VERSION 5.7 ;
BUSBITCHARS "[]" ;
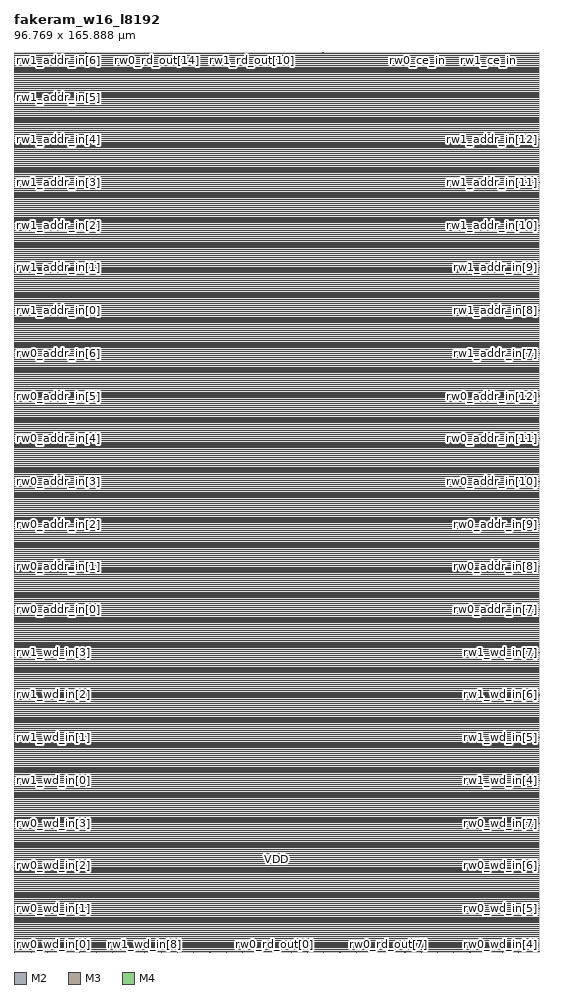
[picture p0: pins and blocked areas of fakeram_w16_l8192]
MACRO fakeram_w16_l8192
  FOREIGN fakeram_w16_l8192 0 0 ;
  SYMMETRY X Y R90 ;
  SIZE 96.769 BY 165.888 ;
  CLASS BLOCK ;
  PIN rw0_wd_in[0]
    DIRECTION INPUT ;
    USE SIGNAL ;
    SHAPE ABUTMENT ;
    PORT
      LAYER M2 ;
      RECT 0.000 0.138 0.036 0.150 ;
    END
  END rw0_wd_in[0]
  PIN rw0_wd_in[1]
    DIRECTION INPUT ;
    USE SIGNAL ;
    SHAPE ABUTMENT ;
    PORT
      LAYER M2 ;
      RECT 0.000 8.010 0.036 8.022 ;
    END
  END rw0_wd_in[1]
  PIN rw0_wd_in[2]
    DIRECTION INPUT ;
    USE SIGNAL ;
    SHAPE ABUTMENT ;
    PORT
      LAYER M2 ;
      RECT 0.000 15.882 0.036 15.894 ;
    END
  END rw0_wd_in[2]
  PIN rw0_wd_in[3]
    DIRECTION INPUT ;
    USE SIGNAL ;
    SHAPE ABUTMENT ;
    PORT
      LAYER M2 ;
      RECT 0.000 23.754 0.036 23.766 ;
    END
  END rw0_wd_in[3]
  PIN rw0_wd_in[4]
    DIRECTION INPUT ;
    USE SIGNAL ;
    SHAPE ABUTMENT ;
    PORT
      LAYER M2 ;
      RECT 96.733 0.138 96.769 0.150 ;
    END
  END rw0_wd_in[4]
  PIN rw0_wd_in[5]
    DIRECTION INPUT ;
    USE SIGNAL ;
    SHAPE ABUTMENT ;
    PORT
      LAYER M2 ;
      RECT 96.733 8.010 96.769 8.022 ;
    END
  END rw0_wd_in[5]
  PIN rw0_wd_in[6]
    DIRECTION INPUT ;
    USE SIGNAL ;
    SHAPE ABUTMENT ;
    PORT
      LAYER M2 ;
      RECT 96.733 15.882 96.769 15.894 ;
    END
  END rw0_wd_in[6]
  PIN rw0_wd_in[7]
    DIRECTION INPUT ;
    USE SIGNAL ;
    SHAPE ABUTMENT ;
    PORT
      LAYER M2 ;
      RECT 96.733 23.754 96.769 23.766 ;
    END
  END rw0_wd_in[7]
  PIN rw0_wd_in[8]
    DIRECTION INPUT ;
    USE SIGNAL ;
    SHAPE ABUTMENT ;
    PORT
      LAYER M3 ;
      RECT 0.161 0.000 0.175 0.042 ;
    END
  END rw0_wd_in[8]
  PIN rw0_wd_in[9]
    DIRECTION INPUT ;
    USE SIGNAL ;
    SHAPE ABUTMENT ;
    PORT
      LAYER M3 ;
      RECT 3.157 0.000 3.171 0.042 ;
    END
  END rw0_wd_in[9]
  PIN rw0_wd_in[10]
    DIRECTION INPUT ;
    USE SIGNAL ;
    SHAPE ABUTMENT ;
    PORT
      LAYER M3 ;
      RECT 6.153 0.000 6.167 0.042 ;
    END
  END rw0_wd_in[10]
  PIN rw0_wd_in[11]
    DIRECTION INPUT ;
    USE SIGNAL ;
    SHAPE ABUTMENT ;
    PORT
      LAYER M3 ;
      RECT 9.149 0.000 9.163 0.042 ;
    END
  END rw0_wd_in[11]
  PIN rw0_wd_in[12]
    DIRECTION INPUT ;
    USE SIGNAL ;
    SHAPE ABUTMENT ;
    PORT
      LAYER M3 ;
      RECT 12.145 0.000 12.159 0.042 ;
    END
  END rw0_wd_in[12]
  PIN rw0_wd_in[13]
    DIRECTION INPUT ;
    USE SIGNAL ;
    SHAPE ABUTMENT ;
    PORT
      LAYER M3 ;
      RECT 15.141 0.000 15.155 0.042 ;
    END
  END rw0_wd_in[13]
  PIN rw0_wd_in[14]
    DIRECTION INPUT ;
    USE SIGNAL ;
    SHAPE ABUTMENT ;
    PORT
      LAYER M3 ;
      RECT 18.137 0.000 18.151 0.042 ;
    END
  END rw0_wd_in[14]
  PIN rw0_wd_in[15]
    DIRECTION INPUT ;
    USE SIGNAL ;
    SHAPE ABUTMENT ;
    PORT
      LAYER M3 ;
      RECT 21.133 0.000 21.147 0.042 ;
    END
  END rw0_wd_in[15]
  PIN rw1_wd_in[0]
    DIRECTION INPUT ;
    USE SIGNAL ;
    SHAPE ABUTMENT ;
    PORT
      LAYER M2 ;
      RECT 0.000 31.626 0.036 31.638 ;
    END
  END rw1_wd_in[0]
  PIN rw1_wd_in[1]
    DIRECTION INPUT ;
    USE SIGNAL ;
    SHAPE ABUTMENT ;
    PORT
      LAYER M2 ;
      RECT 0.000 39.498 0.036 39.510 ;
    END
  END rw1_wd_in[1]
  PIN rw1_wd_in[2]
    DIRECTION INPUT ;
    USE SIGNAL ;
    SHAPE ABUTMENT ;
    PORT
      LAYER M2 ;
      RECT 0.000 47.370 0.036 47.382 ;
    END
  END rw1_wd_in[2]
  PIN rw1_wd_in[3]
    DIRECTION INPUT ;
    USE SIGNAL ;
    SHAPE ABUTMENT ;
    PORT
      LAYER M2 ;
      RECT 0.000 55.242 0.036 55.254 ;
    END
  END rw1_wd_in[3]
  PIN rw1_wd_in[4]
    DIRECTION INPUT ;
    USE SIGNAL ;
    SHAPE ABUTMENT ;
    PORT
      LAYER M2 ;
      RECT 96.733 31.626 96.769 31.638 ;
    END
  END rw1_wd_in[4]
  PIN rw1_wd_in[5]
    DIRECTION INPUT ;
    USE SIGNAL ;
    SHAPE ABUTMENT ;
    PORT
      LAYER M2 ;
      RECT 96.733 39.498 96.769 39.510 ;
    END
  END rw1_wd_in[5]
  PIN rw1_wd_in[6]
    DIRECTION INPUT ;
    USE SIGNAL ;
    SHAPE ABUTMENT ;
    PORT
      LAYER M2 ;
      RECT 96.733 47.370 96.769 47.382 ;
    END
  END rw1_wd_in[6]
  PIN rw1_wd_in[7]
    DIRECTION INPUT ;
    USE SIGNAL ;
    SHAPE ABUTMENT ;
    PORT
      LAYER M2 ;
      RECT 96.733 55.242 96.769 55.254 ;
    END
  END rw1_wd_in[7]
  PIN rw1_wd_in[8]
    DIRECTION INPUT ;
    USE SIGNAL ;
    SHAPE ABUTMENT ;
    PORT
      LAYER M3 ;
      RECT 24.129 0.000 24.143 0.042 ;
    END
  END rw1_wd_in[8]
  PIN rw1_wd_in[9]
    DIRECTION INPUT ;
    USE SIGNAL ;
    SHAPE ABUTMENT ;
    PORT
      LAYER M3 ;
      RECT 27.125 0.000 27.139 0.042 ;
    END
  END rw1_wd_in[9]
  PIN rw1_wd_in[10]
    DIRECTION INPUT ;
    USE SIGNAL ;
    SHAPE ABUTMENT ;
    PORT
      LAYER M3 ;
      RECT 30.121 0.000 30.135 0.042 ;
    END
  END rw1_wd_in[10]
  PIN rw1_wd_in[11]
    DIRECTION INPUT ;
    USE SIGNAL ;
    SHAPE ABUTMENT ;
    PORT
      LAYER M3 ;
      RECT 33.117 0.000 33.131 0.042 ;
    END
  END rw1_wd_in[11]
  PIN rw1_wd_in[12]
    DIRECTION INPUT ;
    USE SIGNAL ;
    SHAPE ABUTMENT ;
    PORT
      LAYER M3 ;
      RECT 36.113 0.000 36.127 0.042 ;
    END
  END rw1_wd_in[12]
  PIN rw1_wd_in[13]
    DIRECTION INPUT ;
    USE SIGNAL ;
    SHAPE ABUTMENT ;
    PORT
      LAYER M3 ;
      RECT 39.109 0.000 39.123 0.042 ;
    END
  END rw1_wd_in[13]
  PIN rw1_wd_in[14]
    DIRECTION INPUT ;
    USE SIGNAL ;
    SHAPE ABUTMENT ;
    PORT
      LAYER M3 ;
      RECT 42.105 0.000 42.119 0.042 ;
    END
  END rw1_wd_in[14]
  PIN rw1_wd_in[15]
    DIRECTION INPUT ;
    USE SIGNAL ;
    SHAPE ABUTMENT ;
    PORT
      LAYER M3 ;
      RECT 45.101 0.000 45.115 0.042 ;
    END
  END rw1_wd_in[15]
  PIN rw0_rd_out[0]
    DIRECTION OUTPUT ;
    USE SIGNAL ;
    SHAPE ABUTMENT ;
    PORT
      LAYER M3 ;
      RECT 48.097 0.000 48.111 0.042 ;
    END
  END rw0_rd_out[0]
  PIN rw0_rd_out[1]
    DIRECTION OUTPUT ;
    USE SIGNAL ;
    SHAPE ABUTMENT ;
    PORT
      LAYER M3 ;
      RECT 51.093 0.000 51.107 0.042 ;
    END
  END rw0_rd_out[1]
  PIN rw0_rd_out[2]
    DIRECTION OUTPUT ;
    USE SIGNAL ;
    SHAPE ABUTMENT ;
    PORT
      LAYER M3 ;
      RECT 54.089 0.000 54.103 0.042 ;
    END
  END rw0_rd_out[2]
  PIN rw0_rd_out[3]
    DIRECTION OUTPUT ;
    USE SIGNAL ;
    SHAPE ABUTMENT ;
    PORT
      LAYER M3 ;
      RECT 57.085 0.000 57.099 0.042 ;
    END
  END rw0_rd_out[3]
  PIN rw0_rd_out[4]
    DIRECTION OUTPUT ;
    USE SIGNAL ;
    SHAPE ABUTMENT ;
    PORT
      LAYER M3 ;
      RECT 60.081 0.000 60.095 0.042 ;
    END
  END rw0_rd_out[4]
  PIN rw0_rd_out[5]
    DIRECTION OUTPUT ;
    USE SIGNAL ;
    SHAPE ABUTMENT ;
    PORT
      LAYER M3 ;
      RECT 63.077 0.000 63.091 0.042 ;
    END
  END rw0_rd_out[5]
  PIN rw0_rd_out[6]
    DIRECTION OUTPUT ;
    USE SIGNAL ;
    SHAPE ABUTMENT ;
    PORT
      LAYER M3 ;
      RECT 66.073 0.000 66.087 0.042 ;
    END
  END rw0_rd_out[6]
  PIN rw0_rd_out[7]
    DIRECTION OUTPUT ;
    USE SIGNAL ;
    SHAPE ABUTMENT ;
    PORT
      LAYER M3 ;
      RECT 69.069 0.000 69.083 0.042 ;
    END
  END rw0_rd_out[7]
  PIN rw0_rd_out[8]
    DIRECTION OUTPUT ;
    USE SIGNAL ;
    SHAPE ABUTMENT ;
    PORT
      LAYER M3 ;
      RECT 0.161 165.846 0.175 165.888 ;
    END
  END rw0_rd_out[8]
  PIN rw0_rd_out[9]
    DIRECTION OUTPUT ;
    USE SIGNAL ;
    SHAPE ABUTMENT ;
    PORT
      LAYER M3 ;
      RECT 4.529 165.846 4.543 165.888 ;
    END
  END rw0_rd_out[9]
  PIN rw0_rd_out[10]
    DIRECTION OUTPUT ;
    USE SIGNAL ;
    SHAPE ABUTMENT ;
    PORT
      LAYER M3 ;
      RECT 8.897 165.846 8.911 165.888 ;
    END
  END rw0_rd_out[10]
  PIN rw0_rd_out[11]
    DIRECTION OUTPUT ;
    USE SIGNAL ;
    SHAPE ABUTMENT ;
    PORT
      LAYER M3 ;
      RECT 13.265 165.846 13.279 165.888 ;
    END
  END rw0_rd_out[11]
  PIN rw0_rd_out[12]
    DIRECTION OUTPUT ;
    USE SIGNAL ;
    SHAPE ABUTMENT ;
    PORT
      LAYER M3 ;
      RECT 17.633 165.846 17.647 165.888 ;
    END
  END rw0_rd_out[12]
  PIN rw0_rd_out[13]
    DIRECTION OUTPUT ;
    USE SIGNAL ;
    SHAPE ABUTMENT ;
    PORT
      LAYER M3 ;
      RECT 22.001 165.846 22.015 165.888 ;
    END
  END rw0_rd_out[13]
  PIN rw0_rd_out[14]
    DIRECTION OUTPUT ;
    USE SIGNAL ;
    SHAPE ABUTMENT ;
    PORT
      LAYER M3 ;
      RECT 26.369 165.846 26.383 165.888 ;
    END
  END rw0_rd_out[14]
  PIN rw0_rd_out[15]
    DIRECTION OUTPUT ;
    USE SIGNAL ;
    SHAPE ABUTMENT ;
    PORT
      LAYER M3 ;
      RECT 30.737 165.846 30.751 165.888 ;
    END
  END rw0_rd_out[15]
  PIN rw1_rd_out[0]
    DIRECTION OUTPUT ;
    USE SIGNAL ;
    SHAPE ABUTMENT ;
    PORT
      LAYER M3 ;
      RECT 72.065 0.000 72.079 0.042 ;
    END
  END rw1_rd_out[0]
  PIN rw1_rd_out[1]
    DIRECTION OUTPUT ;
    USE SIGNAL ;
    SHAPE ABUTMENT ;
    PORT
      LAYER M3 ;
      RECT 75.061 0.000 75.075 0.042 ;
    END
  END rw1_rd_out[1]
  PIN rw1_rd_out[2]
    DIRECTION OUTPUT ;
    USE SIGNAL ;
    SHAPE ABUTMENT ;
    PORT
      LAYER M3 ;
      RECT 78.057 0.000 78.071 0.042 ;
    END
  END rw1_rd_out[2]
  PIN rw1_rd_out[3]
    DIRECTION OUTPUT ;
    USE SIGNAL ;
    SHAPE ABUTMENT ;
    PORT
      LAYER M3 ;
      RECT 81.053 0.000 81.067 0.042 ;
    END
  END rw1_rd_out[3]
  PIN rw1_rd_out[4]
    DIRECTION OUTPUT ;
    USE SIGNAL ;
    SHAPE ABUTMENT ;
    PORT
      LAYER M3 ;
      RECT 84.049 0.000 84.063 0.042 ;
    END
  END rw1_rd_out[4]
  PIN rw1_rd_out[5]
    DIRECTION OUTPUT ;
    USE SIGNAL ;
    SHAPE ABUTMENT ;
    PORT
      LAYER M3 ;
      RECT 87.045 0.000 87.059 0.042 ;
    END
  END rw1_rd_out[5]
  PIN rw1_rd_out[6]
    DIRECTION OUTPUT ;
    USE SIGNAL ;
    SHAPE ABUTMENT ;
    PORT
      LAYER M3 ;
      RECT 90.041 0.000 90.055 0.042 ;
    END
  END rw1_rd_out[6]
  PIN rw1_rd_out[7]
    DIRECTION OUTPUT ;
    USE SIGNAL ;
    SHAPE ABUTMENT ;
    PORT
      LAYER M3 ;
      RECT 93.037 0.000 93.051 0.042 ;
    END
  END rw1_rd_out[7]
  PIN rw1_rd_out[8]
    DIRECTION OUTPUT ;
    USE SIGNAL ;
    SHAPE ABUTMENT ;
    PORT
      LAYER M3 ;
      RECT 35.105 165.846 35.119 165.888 ;
    END
  END rw1_rd_out[8]
  PIN rw1_rd_out[9]
    DIRECTION OUTPUT ;
    USE SIGNAL ;
    SHAPE ABUTMENT ;
    PORT
      LAYER M3 ;
      RECT 39.473 165.846 39.487 165.888 ;
    END
  END rw1_rd_out[9]
  PIN rw1_rd_out[10]
    DIRECTION OUTPUT ;
    USE SIGNAL ;
    SHAPE ABUTMENT ;
    PORT
      LAYER M3 ;
      RECT 43.841 165.846 43.855 165.888 ;
    END
  END rw1_rd_out[10]
  PIN rw1_rd_out[11]
    DIRECTION OUTPUT ;
    USE SIGNAL ;
    SHAPE ABUTMENT ;
    PORT
      LAYER M3 ;
      RECT 48.209 165.846 48.223 165.888 ;
    END
  END rw1_rd_out[11]
  PIN rw1_rd_out[12]
    DIRECTION OUTPUT ;
    USE SIGNAL ;
    SHAPE ABUTMENT ;
    PORT
      LAYER M3 ;
      RECT 52.577 165.846 52.591 165.888 ;
    END
  END rw1_rd_out[12]
  PIN rw1_rd_out[13]
    DIRECTION OUTPUT ;
    USE SIGNAL ;
    SHAPE ABUTMENT ;
    PORT
      LAYER M3 ;
      RECT 56.945 165.846 56.959 165.888 ;
    END
  END rw1_rd_out[13]
  PIN rw1_rd_out[14]
    DIRECTION OUTPUT ;
    USE SIGNAL ;
    SHAPE ABUTMENT ;
    PORT
      LAYER M3 ;
      RECT 61.313 165.846 61.327 165.888 ;
    END
  END rw1_rd_out[14]
  PIN rw1_rd_out[15]
    DIRECTION OUTPUT ;
    USE SIGNAL ;
    SHAPE ABUTMENT ;
    PORT
      LAYER M3 ;
      RECT 65.681 165.846 65.695 165.888 ;
    END
  END rw1_rd_out[15]
  PIN rw0_addr_in[0]
    DIRECTION INPUT ;
    USE SIGNAL ;
    SHAPE ABUTMENT ;
    PORT
      LAYER M2 ;
      RECT 0.000 63.114 0.036 63.126 ;
    END
  END rw0_addr_in[0]
  PIN rw0_addr_in[1]
    DIRECTION INPUT ;
    USE SIGNAL ;
    SHAPE ABUTMENT ;
    PORT
      LAYER M2 ;
      RECT 0.000 70.986 0.036 70.998 ;
    END
  END rw0_addr_in[1]
  PIN rw0_addr_in[2]
    DIRECTION INPUT ;
    USE SIGNAL ;
    SHAPE ABUTMENT ;
    PORT
      LAYER M2 ;
      RECT 0.000 78.858 0.036 78.870 ;
    END
  END rw0_addr_in[2]
  PIN rw0_addr_in[3]
    DIRECTION INPUT ;
    USE SIGNAL ;
    SHAPE ABUTMENT ;
    PORT
      LAYER M2 ;
      RECT 0.000 86.730 0.036 86.742 ;
    END
  END rw0_addr_in[3]
  PIN rw0_addr_in[4]
    DIRECTION INPUT ;
    USE SIGNAL ;
    SHAPE ABUTMENT ;
    PORT
      LAYER M2 ;
      RECT 0.000 94.602 0.036 94.614 ;
    END
  END rw0_addr_in[4]
  PIN rw0_addr_in[5]
    DIRECTION INPUT ;
    USE SIGNAL ;
    SHAPE ABUTMENT ;
    PORT
      LAYER M2 ;
      RECT 0.000 102.474 0.036 102.486 ;
    END
  END rw0_addr_in[5]
  PIN rw0_addr_in[6]
    DIRECTION INPUT ;
    USE SIGNAL ;
    SHAPE ABUTMENT ;
    PORT
      LAYER M2 ;
      RECT 0.000 110.346 0.036 110.358 ;
    END
  END rw0_addr_in[6]
  PIN rw0_addr_in[7]
    DIRECTION INPUT ;
    USE SIGNAL ;
    SHAPE ABUTMENT ;
    PORT
      LAYER M2 ;
      RECT 96.733 63.114 96.769 63.126 ;
    END
  END rw0_addr_in[7]
  PIN rw0_addr_in[8]
    DIRECTION INPUT ;
    USE SIGNAL ;
    SHAPE ABUTMENT ;
    PORT
      LAYER M2 ;
      RECT 96.733 70.986 96.769 70.998 ;
    END
  END rw0_addr_in[8]
  PIN rw0_addr_in[9]
    DIRECTION INPUT ;
    USE SIGNAL ;
    SHAPE ABUTMENT ;
    PORT
      LAYER M2 ;
      RECT 96.733 78.858 96.769 78.870 ;
    END
  END rw0_addr_in[9]
  PIN rw0_addr_in[10]
    DIRECTION INPUT ;
    USE SIGNAL ;
    SHAPE ABUTMENT ;
    PORT
      LAYER M2 ;
      RECT 96.733 86.730 96.769 86.742 ;
    END
  END rw0_addr_in[10]
  PIN rw0_addr_in[11]
    DIRECTION INPUT ;
    USE SIGNAL ;
    SHAPE ABUTMENT ;
    PORT
      LAYER M2 ;
      RECT 96.733 94.602 96.769 94.614 ;
    END
  END rw0_addr_in[11]
  PIN rw0_addr_in[12]
    DIRECTION INPUT ;
    USE SIGNAL ;
    SHAPE ABUTMENT ;
    PORT
      LAYER M2 ;
      RECT 96.733 102.474 96.769 102.486 ;
    END
  END rw0_addr_in[12]
  PIN rw1_addr_in[0]
    DIRECTION INPUT ;
    USE SIGNAL ;
    SHAPE ABUTMENT ;
    PORT
      LAYER M2 ;
      RECT 0.000 118.218 0.036 118.230 ;
    END
  END rw1_addr_in[0]
  PIN rw1_addr_in[1]
    DIRECTION INPUT ;
    USE SIGNAL ;
    SHAPE ABUTMENT ;
    PORT
      LAYER M2 ;
      RECT 0.000 126.090 0.036 126.102 ;
    END
  END rw1_addr_in[1]
  PIN rw1_addr_in[2]
    DIRECTION INPUT ;
    USE SIGNAL ;
    SHAPE ABUTMENT ;
    PORT
      LAYER M2 ;
      RECT 0.000 133.962 0.036 133.974 ;
    END
  END rw1_addr_in[2]
  PIN rw1_addr_in[3]
    DIRECTION INPUT ;
    USE SIGNAL ;
    SHAPE ABUTMENT ;
    PORT
      LAYER M2 ;
      RECT 0.000 141.834 0.036 141.846 ;
    END
  END rw1_addr_in[3]
  PIN rw1_addr_in[4]
    DIRECTION INPUT ;
    USE SIGNAL ;
    SHAPE ABUTMENT ;
    PORT
      LAYER M2 ;
      RECT 0.000 149.706 0.036 149.718 ;
    END
  END rw1_addr_in[4]
  PIN rw1_addr_in[5]
    DIRECTION INPUT ;
    USE SIGNAL ;
    SHAPE ABUTMENT ;
    PORT
      LAYER M2 ;
      RECT 0.000 157.578 0.036 157.590 ;
    END
  END rw1_addr_in[5]
  PIN rw1_addr_in[6]
    DIRECTION INPUT ;
    USE SIGNAL ;
    SHAPE ABUTMENT ;
    PORT
      LAYER M2 ;
      RECT 0.000 165.450 0.036 165.462 ;
    END
  END rw1_addr_in[6]
  PIN rw1_addr_in[7]
    DIRECTION INPUT ;
    USE SIGNAL ;
    SHAPE ABUTMENT ;
    PORT
      LAYER M2 ;
      RECT 96.733 110.346 96.769 110.358 ;
    END
  END rw1_addr_in[7]
  PIN rw1_addr_in[8]
    DIRECTION INPUT ;
    USE SIGNAL ;
    SHAPE ABUTMENT ;
    PORT
      LAYER M2 ;
      RECT 96.733 118.218 96.769 118.230 ;
    END
  END rw1_addr_in[8]
  PIN rw1_addr_in[9]
    DIRECTION INPUT ;
    USE SIGNAL ;
    SHAPE ABUTMENT ;
    PORT
      LAYER M2 ;
      RECT 96.733 126.090 96.769 126.102 ;
    END
  END rw1_addr_in[9]
  PIN rw1_addr_in[10]
    DIRECTION INPUT ;
    USE SIGNAL ;
    SHAPE ABUTMENT ;
    PORT
      LAYER M2 ;
      RECT 96.733 133.962 96.769 133.974 ;
    END
  END rw1_addr_in[10]
  PIN rw1_addr_in[11]
    DIRECTION INPUT ;
    USE SIGNAL ;
    SHAPE ABUTMENT ;
    PORT
      LAYER M2 ;
      RECT 96.733 141.834 96.769 141.846 ;
    END
  END rw1_addr_in[11]
  PIN rw1_addr_in[12]
    DIRECTION INPUT ;
    USE SIGNAL ;
    SHAPE ABUTMENT ;
    PORT
      LAYER M2 ;
      RECT 96.733 149.706 96.769 149.718 ;
    END
  END rw1_addr_in[12]
  PIN rw0_we_in
    DIRECTION INPUT ;
    USE SIGNAL ;
    SHAPE ABUTMENT ;
    PORT
      LAYER M3 ;
      RECT 70.049 165.846 70.063 165.888 ;
    END
  END rw0_we_in
  PIN rw0_ce_in
    DIRECTION INPUT ;
    USE SIGNAL ;
    SHAPE ABUTMENT ;
    PORT
      LAYER M3 ;
      RECT 74.417 165.846 74.431 165.888 ;
    END
  END rw0_ce_in
  PIN rw0_clk
    DIRECTION INPUT ;
    USE SIGNAL ;
    SHAPE ABUTMENT ;
    PORT
      LAYER M3 ;
      RECT 78.785 165.846 78.799 165.888 ;
    END
  END rw0_clk
  PIN rw1_we_in
    DIRECTION INPUT ;
    USE SIGNAL ;
    SHAPE ABUTMENT ;
    PORT
      LAYER M3 ;
      RECT 83.153 165.846 83.167 165.888 ;
    END
  END rw1_we_in
  PIN rw1_ce_in
    DIRECTION INPUT ;
    USE SIGNAL ;
    SHAPE ABUTMENT ;
    PORT
      LAYER M3 ;
      RECT 87.521 165.846 87.535 165.888 ;
    END
  END rw1_ce_in
  PIN rw1_clk
    DIRECTION INPUT ;
    USE SIGNAL ;
    SHAPE ABUTMENT ;
    PORT
      LAYER M3 ;
      RECT 91.889 165.846 91.903 165.888 ;
    END
  END rw1_clk
  PIN VSS
    DIRECTION INOUT ;
    USE GROUND ;
    PORT
      LAYER M4 ;
      RECT 0.168 0.120 96.601 0.168 ;
      RECT 0.168 0.504 96.601 0.552 ;
      RECT 0.168 0.888 96.601 0.936 ;
      RECT 0.168 1.272 96.601 1.320 ;
      RECT 0.168 1.656 96.601 1.704 ;
      RECT 0.168 2.040 96.601 2.088 ;
      RECT 0.168 2.424 96.601 2.472 ;
      RECT 0.168 2.808 96.601 2.856 ;
      RECT 0.168 3.192 96.601 3.240 ;
      RECT 0.168 3.576 96.601 3.624 ;
      RECT 0.168 3.960 96.601 4.008 ;
      RECT 0.168 4.344 96.601 4.392 ;
      RECT 0.168 4.728 96.601 4.776 ;
      RECT 0.168 5.112 96.601 5.160 ;
      RECT 0.168 5.496 96.601 5.544 ;
      RECT 0.168 5.880 96.601 5.928 ;
      RECT 0.168 6.264 96.601 6.312 ;
      RECT 0.168 6.648 96.601 6.696 ;
      RECT 0.168 7.032 96.601 7.080 ;
      RECT 0.168 7.416 96.601 7.464 ;
      RECT 0.168 7.800 96.601 7.848 ;
      RECT 0.168 8.184 96.601 8.232 ;
      RECT 0.168 8.568 96.601 8.616 ;
      RECT 0.168 8.952 96.601 9.000 ;
      RECT 0.168 9.336 96.601 9.384 ;
      RECT 0.168 9.720 96.601 9.768 ;
      RECT 0.168 10.104 96.601 10.152 ;
      RECT 0.168 10.488 96.601 10.536 ;
      RECT 0.168 10.872 96.601 10.920 ;
      RECT 0.168 11.256 96.601 11.304 ;
      RECT 0.168 11.640 96.601 11.688 ;
      RECT 0.168 12.024 96.601 12.072 ;
      RECT 0.168 12.408 96.601 12.456 ;
      RECT 0.168 12.792 96.601 12.840 ;
      RECT 0.168 13.176 96.601 13.224 ;
      RECT 0.168 13.560 96.601 13.608 ;
      RECT 0.168 13.944 96.601 13.992 ;
      RECT 0.168 14.328 96.601 14.376 ;
      RECT 0.168 14.712 96.601 14.760 ;
      RECT 0.168 15.096 96.601 15.144 ;
      RECT 0.168 15.480 96.601 15.528 ;
      RECT 0.168 15.864 96.601 15.912 ;
      RECT 0.168 16.248 96.601 16.296 ;
      RECT 0.168 16.632 96.601 16.680 ;
      RECT 0.168 17.016 96.601 17.064 ;
      RECT 0.168 17.400 96.601 17.448 ;
      RECT 0.168 17.784 96.601 17.832 ;
      RECT 0.168 18.168 96.601 18.216 ;
      RECT 0.168 18.552 96.601 18.600 ;
      RECT 0.168 18.936 96.601 18.984 ;
      RECT 0.168 19.320 96.601 19.368 ;
      RECT 0.168 19.704 96.601 19.752 ;
      RECT 0.168 20.088 96.601 20.136 ;
      RECT 0.168 20.472 96.601 20.520 ;
      RECT 0.168 20.856 96.601 20.904 ;
      RECT 0.168 21.240 96.601 21.288 ;
      RECT 0.168 21.624 96.601 21.672 ;
      RECT 0.168 22.008 96.601 22.056 ;
      RECT 0.168 22.392 96.601 22.440 ;
      RECT 0.168 22.776 96.601 22.824 ;
      RECT 0.168 23.160 96.601 23.208 ;
      RECT 0.168 23.544 96.601 23.592 ;
      RECT 0.168 23.928 96.601 23.976 ;
      RECT 0.168 24.312 96.601 24.360 ;
      RECT 0.168 24.696 96.601 24.744 ;
      RECT 0.168 25.080 96.601 25.128 ;
      RECT 0.168 25.464 96.601 25.512 ;
      RECT 0.168 25.848 96.601 25.896 ;
      RECT 0.168 26.232 96.601 26.280 ;
      RECT 0.168 26.616 96.601 26.664 ;
      RECT 0.168 27.000 96.601 27.048 ;
      RECT 0.168 27.384 96.601 27.432 ;
      RECT 0.168 27.768 96.601 27.816 ;
      RECT 0.168 28.152 96.601 28.200 ;
      RECT 0.168 28.536 96.601 28.584 ;
      RECT 0.168 28.920 96.601 28.968 ;
      RECT 0.168 29.304 96.601 29.352 ;
      RECT 0.168 29.688 96.601 29.736 ;
      RECT 0.168 30.072 96.601 30.120 ;
      RECT 0.168 30.456 96.601 30.504 ;
      RECT 0.168 30.840 96.601 30.888 ;
      RECT 0.168 31.224 96.601 31.272 ;
      RECT 0.168 31.608 96.601 31.656 ;
      RECT 0.168 31.992 96.601 32.040 ;
      RECT 0.168 32.376 96.601 32.424 ;
      RECT 0.168 32.760 96.601 32.808 ;
      RECT 0.168 33.144 96.601 33.192 ;
      RECT 0.168 33.528 96.601 33.576 ;
      RECT 0.168 33.912 96.601 33.960 ;
      RECT 0.168 34.296 96.601 34.344 ;
      RECT 0.168 34.680 96.601 34.728 ;
      RECT 0.168 35.064 96.601 35.112 ;
      RECT 0.168 35.448 96.601 35.496 ;
      RECT 0.168 35.832 96.601 35.880 ;
      RECT 0.168 36.216 96.601 36.264 ;
      RECT 0.168 36.600 96.601 36.648 ;
      RECT 0.168 36.984 96.601 37.032 ;
      RECT 0.168 37.368 96.601 37.416 ;
      RECT 0.168 37.752 96.601 37.800 ;
      RECT 0.168 38.136 96.601 38.184 ;
      RECT 0.168 38.520 96.601 38.568 ;
      RECT 0.168 38.904 96.601 38.952 ;
      RECT 0.168 39.288 96.601 39.336 ;
      RECT 0.168 39.672 96.601 39.720 ;
      RECT 0.168 40.056 96.601 40.104 ;
      RECT 0.168 40.440 96.601 40.488 ;
      RECT 0.168 40.824 96.601 40.872 ;
      RECT 0.168 41.208 96.601 41.256 ;
      RECT 0.168 41.592 96.601 41.640 ;
      RECT 0.168 41.976 96.601 42.024 ;
      RECT 0.168 42.360 96.601 42.408 ;
      RECT 0.168 42.744 96.601 42.792 ;
      RECT 0.168 43.128 96.601 43.176 ;
      RECT 0.168 43.512 96.601 43.560 ;
      RECT 0.168 43.896 96.601 43.944 ;
      RECT 0.168 44.280 96.601 44.328 ;
      RECT 0.168 44.664 96.601 44.712 ;
      RECT 0.168 45.048 96.601 45.096 ;
      RECT 0.168 45.432 96.601 45.480 ;
      RECT 0.168 45.816 96.601 45.864 ;
      RECT 0.168 46.200 96.601 46.248 ;
      RECT 0.168 46.584 96.601 46.632 ;
      RECT 0.168 46.968 96.601 47.016 ;
      RECT 0.168 47.352 96.601 47.400 ;
      RECT 0.168 47.736 96.601 47.784 ;
      RECT 0.168 48.120 96.601 48.168 ;
      RECT 0.168 48.504 96.601 48.552 ;
      RECT 0.168 48.888 96.601 48.936 ;
      RECT 0.168 49.272 96.601 49.320 ;
      RECT 0.168 49.656 96.601 49.704 ;
      RECT 0.168 50.040 96.601 50.088 ;
      RECT 0.168 50.424 96.601 50.472 ;
      RECT 0.168 50.808 96.601 50.856 ;
      RECT 0.168 51.192 96.601 51.240 ;
      RECT 0.168 51.576 96.601 51.624 ;
      RECT 0.168 51.960 96.601 52.008 ;
      RECT 0.168 52.344 96.601 52.392 ;
      RECT 0.168 52.728 96.601 52.776 ;
      RECT 0.168 53.112 96.601 53.160 ;
      RECT 0.168 53.496 96.601 53.544 ;
      RECT 0.168 53.880 96.601 53.928 ;
      RECT 0.168 54.264 96.601 54.312 ;
      RECT 0.168 54.648 96.601 54.696 ;
      RECT 0.168 55.032 96.601 55.080 ;
      RECT 0.168 55.416 96.601 55.464 ;
      RECT 0.168 55.800 96.601 55.848 ;
      RECT 0.168 56.184 96.601 56.232 ;
      RECT 0.168 56.568 96.601 56.616 ;
      RECT 0.168 56.952 96.601 57.000 ;
      RECT 0.168 57.336 96.601 57.384 ;
      RECT 0.168 57.720 96.601 57.768 ;
      RECT 0.168 58.104 96.601 58.152 ;
      RECT 0.168 58.488 96.601 58.536 ;
      RECT 0.168 58.872 96.601 58.920 ;
      RECT 0.168 59.256 96.601 59.304 ;
      RECT 0.168 59.640 96.601 59.688 ;
      RECT 0.168 60.024 96.601 60.072 ;
      RECT 0.168 60.408 96.601 60.456 ;
      RECT 0.168 60.792 96.601 60.840 ;
      RECT 0.168 61.176 96.601 61.224 ;
      RECT 0.168 61.560 96.601 61.608 ;
      RECT 0.168 61.944 96.601 61.992 ;
      RECT 0.168 62.328 96.601 62.376 ;
      RECT 0.168 62.712 96.601 62.760 ;
      RECT 0.168 63.096 96.601 63.144 ;
      RECT 0.168 63.480 96.601 63.528 ;
      RECT 0.168 63.864 96.601 63.912 ;
      RECT 0.168 64.248 96.601 64.296 ;
      RECT 0.168 64.632 96.601 64.680 ;
      RECT 0.168 65.016 96.601 65.064 ;
      RECT 0.168 65.400 96.601 65.448 ;
      RECT 0.168 65.784 96.601 65.832 ;
      RECT 0.168 66.168 96.601 66.216 ;
      RECT 0.168 66.552 96.601 66.600 ;
      RECT 0.168 66.936 96.601 66.984 ;
      RECT 0.168 67.320 96.601 67.368 ;
      RECT 0.168 67.704 96.601 67.752 ;
      RECT 0.168 68.088 96.601 68.136 ;
      RECT 0.168 68.472 96.601 68.520 ;
      RECT 0.168 68.856 96.601 68.904 ;
      RECT 0.168 69.240 96.601 69.288 ;
      RECT 0.168 69.624 96.601 69.672 ;
      RECT 0.168 70.008 96.601 70.056 ;
      RECT 0.168 70.392 96.601 70.440 ;
      RECT 0.168 70.776 96.601 70.824 ;
      RECT 0.168 71.160 96.601 71.208 ;
      RECT 0.168 71.544 96.601 71.592 ;
      RECT 0.168 71.928 96.601 71.976 ;
      RECT 0.168 72.312 96.601 72.360 ;
      RECT 0.168 72.696 96.601 72.744 ;
      RECT 0.168 73.080 96.601 73.128 ;
      RECT 0.168 73.464 96.601 73.512 ;
      RECT 0.168 73.848 96.601 73.896 ;
      RECT 0.168 74.232 96.601 74.280 ;
      RECT 0.168 74.616 96.601 74.664 ;
      RECT 0.168 75.000 96.601 75.048 ;
      RECT 0.168 75.384 96.601 75.432 ;
      RECT 0.168 75.768 96.601 75.816 ;
      RECT 0.168 76.152 96.601 76.200 ;
      RECT 0.168 76.536 96.601 76.584 ;
      RECT 0.168 76.920 96.601 76.968 ;
      RECT 0.168 77.304 96.601 77.352 ;
      RECT 0.168 77.688 96.601 77.736 ;
      RECT 0.168 78.072 96.601 78.120 ;
      RECT 0.168 78.456 96.601 78.504 ;
      RECT 0.168 78.840 96.601 78.888 ;
      RECT 0.168 79.224 96.601 79.272 ;
      RECT 0.168 79.608 96.601 79.656 ;
      RECT 0.168 79.992 96.601 80.040 ;
      RECT 0.168 80.376 96.601 80.424 ;
      RECT 0.168 80.760 96.601 80.808 ;
      RECT 0.168 81.144 96.601 81.192 ;
      RECT 0.168 81.528 96.601 81.576 ;
      RECT 0.168 81.912 96.601 81.960 ;
      RECT 0.168 82.296 96.601 82.344 ;
      RECT 0.168 82.680 96.601 82.728 ;
      RECT 0.168 83.064 96.601 83.112 ;
      RECT 0.168 83.448 96.601 83.496 ;
      RECT 0.168 83.832 96.601 83.880 ;
      RECT 0.168 84.216 96.601 84.264 ;
      RECT 0.168 84.600 96.601 84.648 ;
      RECT 0.168 84.984 96.601 85.032 ;
      RECT 0.168 85.368 96.601 85.416 ;
      RECT 0.168 85.752 96.601 85.800 ;
      RECT 0.168 86.136 96.601 86.184 ;
      RECT 0.168 86.520 96.601 86.568 ;
      RECT 0.168 86.904 96.601 86.952 ;
      RECT 0.168 87.288 96.601 87.336 ;
      RECT 0.168 87.672 96.601 87.720 ;
      RECT 0.168 88.056 96.601 88.104 ;
      RECT 0.168 88.440 96.601 88.488 ;
      RECT 0.168 88.824 96.601 88.872 ;
      RECT 0.168 89.208 96.601 89.256 ;
      RECT 0.168 89.592 96.601 89.640 ;
      RECT 0.168 89.976 96.601 90.024 ;
      RECT 0.168 90.360 96.601 90.408 ;
      RECT 0.168 90.744 96.601 90.792 ;
      RECT 0.168 91.128 96.601 91.176 ;
      RECT 0.168 91.512 96.601 91.560 ;
      RECT 0.168 91.896 96.601 91.944 ;
      RECT 0.168 92.280 96.601 92.328 ;
      RECT 0.168 92.664 96.601 92.712 ;
      RECT 0.168 93.048 96.601 93.096 ;
      RECT 0.168 93.432 96.601 93.480 ;
      RECT 0.168 93.816 96.601 93.864 ;
      RECT 0.168 94.200 96.601 94.248 ;
      RECT 0.168 94.584 96.601 94.632 ;
      RECT 0.168 94.968 96.601 95.016 ;
      RECT 0.168 95.352 96.601 95.400 ;
      RECT 0.168 95.736 96.601 95.784 ;
      RECT 0.168 96.120 96.601 96.168 ;
      RECT 0.168 96.504 96.601 96.552 ;
      RECT 0.168 96.888 96.601 96.936 ;
      RECT 0.168 97.272 96.601 97.320 ;
      RECT 0.168 97.656 96.601 97.704 ;
      RECT 0.168 98.040 96.601 98.088 ;
      RECT 0.168 98.424 96.601 98.472 ;
      RECT 0.168 98.808 96.601 98.856 ;
      RECT 0.168 99.192 96.601 99.240 ;
      RECT 0.168 99.576 96.601 99.624 ;
      RECT 0.168 99.960 96.601 100.008 ;
      RECT 0.168 100.344 96.601 100.392 ;
      RECT 0.168 100.728 96.601 100.776 ;
      RECT 0.168 101.112 96.601 101.160 ;
      RECT 0.168 101.496 96.601 101.544 ;
      RECT 0.168 101.880 96.601 101.928 ;
      RECT 0.168 102.264 96.601 102.312 ;
      RECT 0.168 102.648 96.601 102.696 ;
      RECT 0.168 103.032 96.601 103.080 ;
      RECT 0.168 103.416 96.601 103.464 ;
      RECT 0.168 103.800 96.601 103.848 ;
      RECT 0.168 104.184 96.601 104.232 ;
      RECT 0.168 104.568 96.601 104.616 ;
      RECT 0.168 104.952 96.601 105.000 ;
      RECT 0.168 105.336 96.601 105.384 ;
      RECT 0.168 105.720 96.601 105.768 ;
      RECT 0.168 106.104 96.601 106.152 ;
      RECT 0.168 106.488 96.601 106.536 ;
      RECT 0.168 106.872 96.601 106.920 ;
      RECT 0.168 107.256 96.601 107.304 ;
      RECT 0.168 107.640 96.601 107.688 ;
      RECT 0.168 108.024 96.601 108.072 ;
      RECT 0.168 108.408 96.601 108.456 ;
      RECT 0.168 108.792 96.601 108.840 ;
      RECT 0.168 109.176 96.601 109.224 ;
      RECT 0.168 109.560 96.601 109.608 ;
      RECT 0.168 109.944 96.601 109.992 ;
      RECT 0.168 110.328 96.601 110.376 ;
      RECT 0.168 110.712 96.601 110.760 ;
      RECT 0.168 111.096 96.601 111.144 ;
      RECT 0.168 111.480 96.601 111.528 ;
      RECT 0.168 111.864 96.601 111.912 ;
      RECT 0.168 112.248 96.601 112.296 ;
      RECT 0.168 112.632 96.601 112.680 ;
      RECT 0.168 113.016 96.601 113.064 ;
      RECT 0.168 113.400 96.601 113.448 ;
      RECT 0.168 113.784 96.601 113.832 ;
      RECT 0.168 114.168 96.601 114.216 ;
      RECT 0.168 114.552 96.601 114.600 ;
      RECT 0.168 114.936 96.601 114.984 ;
      RECT 0.168 115.320 96.601 115.368 ;
      RECT 0.168 115.704 96.601 115.752 ;
      RECT 0.168 116.088 96.601 116.136 ;
      RECT 0.168 116.472 96.601 116.520 ;
      RECT 0.168 116.856 96.601 116.904 ;
      RECT 0.168 117.240 96.601 117.288 ;
      RECT 0.168 117.624 96.601 117.672 ;
      RECT 0.168 118.008 96.601 118.056 ;
      RECT 0.168 118.392 96.601 118.440 ;
      RECT 0.168 118.776 96.601 118.824 ;
      RECT 0.168 119.160 96.601 119.208 ;
      RECT 0.168 119.544 96.601 119.592 ;
      RECT 0.168 119.928 96.601 119.976 ;
      RECT 0.168 120.312 96.601 120.360 ;
      RECT 0.168 120.696 96.601 120.744 ;
      RECT 0.168 121.080 96.601 121.128 ;
      RECT 0.168 121.464 96.601 121.512 ;
      RECT 0.168 121.848 96.601 121.896 ;
      RECT 0.168 122.232 96.601 122.280 ;
      RECT 0.168 122.616 96.601 122.664 ;
      RECT 0.168 123.000 96.601 123.048 ;
      RECT 0.168 123.384 96.601 123.432 ;
      RECT 0.168 123.768 96.601 123.816 ;
      RECT 0.168 124.152 96.601 124.200 ;
      RECT 0.168 124.536 96.601 124.584 ;
      RECT 0.168 124.920 96.601 124.968 ;
      RECT 0.168 125.304 96.601 125.352 ;
      RECT 0.168 125.688 96.601 125.736 ;
      RECT 0.168 126.072 96.601 126.120 ;
      RECT 0.168 126.456 96.601 126.504 ;
      RECT 0.168 126.840 96.601 126.888 ;
      RECT 0.168 127.224 96.601 127.272 ;
      RECT 0.168 127.608 96.601 127.656 ;
      RECT 0.168 127.992 96.601 128.040 ;
      RECT 0.168 128.376 96.601 128.424 ;
      RECT 0.168 128.760 96.601 128.808 ;
      RECT 0.168 129.144 96.601 129.192 ;
      RECT 0.168 129.528 96.601 129.576 ;
      RECT 0.168 129.912 96.601 129.960 ;
      RECT 0.168 130.296 96.601 130.344 ;
      RECT 0.168 130.680 96.601 130.728 ;
      RECT 0.168 131.064 96.601 131.112 ;
      RECT 0.168 131.448 96.601 131.496 ;
      RECT 0.168 131.832 96.601 131.880 ;
      RECT 0.168 132.216 96.601 132.264 ;
      RECT 0.168 132.600 96.601 132.648 ;
      RECT 0.168 132.984 96.601 133.032 ;
      RECT 0.168 133.368 96.601 133.416 ;
      RECT 0.168 133.752 96.601 133.800 ;
      RECT 0.168 134.136 96.601 134.184 ;
      RECT 0.168 134.520 96.601 134.568 ;
      RECT 0.168 134.904 96.601 134.952 ;
      RECT 0.168 135.288 96.601 135.336 ;
      RECT 0.168 135.672 96.601 135.720 ;
      RECT 0.168 136.056 96.601 136.104 ;
      RECT 0.168 136.440 96.601 136.488 ;
      RECT 0.168 136.824 96.601 136.872 ;
      RECT 0.168 137.208 96.601 137.256 ;
      RECT 0.168 137.592 96.601 137.640 ;
      RECT 0.168 137.976 96.601 138.024 ;
      RECT 0.168 138.360 96.601 138.408 ;
      RECT 0.168 138.744 96.601 138.792 ;
      RECT 0.168 139.128 96.601 139.176 ;
      RECT 0.168 139.512 96.601 139.560 ;
      RECT 0.168 139.896 96.601 139.944 ;
      RECT 0.168 140.280 96.601 140.328 ;
      RECT 0.168 140.664 96.601 140.712 ;
      RECT 0.168 141.048 96.601 141.096 ;
      RECT 0.168 141.432 96.601 141.480 ;
      RECT 0.168 141.816 96.601 141.864 ;
      RECT 0.168 142.200 96.601 142.248 ;
      RECT 0.168 142.584 96.601 142.632 ;
      RECT 0.168 142.968 96.601 143.016 ;
      RECT 0.168 143.352 96.601 143.400 ;
      RECT 0.168 143.736 96.601 143.784 ;
      RECT 0.168 144.120 96.601 144.168 ;
      RECT 0.168 144.504 96.601 144.552 ;
      RECT 0.168 144.888 96.601 144.936 ;
      RECT 0.168 145.272 96.601 145.320 ;
      RECT 0.168 145.656 96.601 145.704 ;
      RECT 0.168 146.040 96.601 146.088 ;
      RECT 0.168 146.424 96.601 146.472 ;
      RECT 0.168 146.808 96.601 146.856 ;
      RECT 0.168 147.192 96.601 147.240 ;
      RECT 0.168 147.576 96.601 147.624 ;
      RECT 0.168 147.960 96.601 148.008 ;
      RECT 0.168 148.344 96.601 148.392 ;
      RECT 0.168 148.728 96.601 148.776 ;
      RECT 0.168 149.112 96.601 149.160 ;
      RECT 0.168 149.496 96.601 149.544 ;
      RECT 0.168 149.880 96.601 149.928 ;
      RECT 0.168 150.264 96.601 150.312 ;
      RECT 0.168 150.648 96.601 150.696 ;
      RECT 0.168 151.032 96.601 151.080 ;
      RECT 0.168 151.416 96.601 151.464 ;
      RECT 0.168 151.800 96.601 151.848 ;
      RECT 0.168 152.184 96.601 152.232 ;
      RECT 0.168 152.568 96.601 152.616 ;
      RECT 0.168 152.952 96.601 153.000 ;
      RECT 0.168 153.336 96.601 153.384 ;
      RECT 0.168 153.720 96.601 153.768 ;
      RECT 0.168 154.104 96.601 154.152 ;
      RECT 0.168 154.488 96.601 154.536 ;
      RECT 0.168 154.872 96.601 154.920 ;
      RECT 0.168 155.256 96.601 155.304 ;
      RECT 0.168 155.640 96.601 155.688 ;
      RECT 0.168 156.024 96.601 156.072 ;
      RECT 0.168 156.408 96.601 156.456 ;
      RECT 0.168 156.792 96.601 156.840 ;
      RECT 0.168 157.176 96.601 157.224 ;
      RECT 0.168 157.560 96.601 157.608 ;
      RECT 0.168 157.944 96.601 157.992 ;
      RECT 0.168 158.328 96.601 158.376 ;
      RECT 0.168 158.712 96.601 158.760 ;
      RECT 0.168 159.096 96.601 159.144 ;
      RECT 0.168 159.480 96.601 159.528 ;
      RECT 0.168 159.864 96.601 159.912 ;
      RECT 0.168 160.248 96.601 160.296 ;
      RECT 0.168 160.632 96.601 160.680 ;
      RECT 0.168 161.016 96.601 161.064 ;
      RECT 0.168 161.400 96.601 161.448 ;
      RECT 0.168 161.784 96.601 161.832 ;
      RECT 0.168 162.168 96.601 162.216 ;
      RECT 0.168 162.552 96.601 162.600 ;
      RECT 0.168 162.936 96.601 162.984 ;
      RECT 0.168 163.320 96.601 163.368 ;
      RECT 0.168 163.704 96.601 163.752 ;
      RECT 0.168 164.088 96.601 164.136 ;
      RECT 0.168 164.472 96.601 164.520 ;
      RECT 0.168 164.856 96.601 164.904 ;
      RECT 0.168 165.240 96.601 165.288 ;
      RECT 0.168 165.624 96.601 165.672 ;
    END
  END VSS
  PIN VDD
    DIRECTION INOUT ;
    USE POWER ;
    PORT
      LAYER M4 ;
      RECT 0.168 0.120 96.601 0.168 ;
      RECT 0.168 0.504 96.601 0.552 ;
      RECT 0.168 0.888 96.601 0.936 ;
      RECT 0.168 1.272 96.601 1.320 ;
      RECT 0.168 1.656 96.601 1.704 ;
      RECT 0.168 2.040 96.601 2.088 ;
      RECT 0.168 2.424 96.601 2.472 ;
      RECT 0.168 2.808 96.601 2.856 ;
      RECT 0.168 3.192 96.601 3.240 ;
      RECT 0.168 3.576 96.601 3.624 ;
      RECT 0.168 3.960 96.601 4.008 ;
      RECT 0.168 4.344 96.601 4.392 ;
      RECT 0.168 4.728 96.601 4.776 ;
      RECT 0.168 5.112 96.601 5.160 ;
      RECT 0.168 5.496 96.601 5.544 ;
      RECT 0.168 5.880 96.601 5.928 ;
      RECT 0.168 6.264 96.601 6.312 ;
      RECT 0.168 6.648 96.601 6.696 ;
      RECT 0.168 7.032 96.601 7.080 ;
      RECT 0.168 7.416 96.601 7.464 ;
      RECT 0.168 7.800 96.601 7.848 ;
      RECT 0.168 8.184 96.601 8.232 ;
      RECT 0.168 8.568 96.601 8.616 ;
      RECT 0.168 8.952 96.601 9.000 ;
      RECT 0.168 9.336 96.601 9.384 ;
      RECT 0.168 9.720 96.601 9.768 ;
      RECT 0.168 10.104 96.601 10.152 ;
      RECT 0.168 10.488 96.601 10.536 ;
      RECT 0.168 10.872 96.601 10.920 ;
      RECT 0.168 11.256 96.601 11.304 ;
      RECT 0.168 11.640 96.601 11.688 ;
      RECT 0.168 12.024 96.601 12.072 ;
      RECT 0.168 12.408 96.601 12.456 ;
      RECT 0.168 12.792 96.601 12.840 ;
      RECT 0.168 13.176 96.601 13.224 ;
      RECT 0.168 13.560 96.601 13.608 ;
      RECT 0.168 13.944 96.601 13.992 ;
      RECT 0.168 14.328 96.601 14.376 ;
      RECT 0.168 14.712 96.601 14.760 ;
      RECT 0.168 15.096 96.601 15.144 ;
      RECT 0.168 15.480 96.601 15.528 ;
      RECT 0.168 15.864 96.601 15.912 ;
      RECT 0.168 16.248 96.601 16.296 ;
      RECT 0.168 16.632 96.601 16.680 ;
      RECT 0.168 17.016 96.601 17.064 ;
      RECT 0.168 17.400 96.601 17.448 ;
      RECT 0.168 17.784 96.601 17.832 ;
      RECT 0.168 18.168 96.601 18.216 ;
      RECT 0.168 18.552 96.601 18.600 ;
      RECT 0.168 18.936 96.601 18.984 ;
      RECT 0.168 19.320 96.601 19.368 ;
      RECT 0.168 19.704 96.601 19.752 ;
      RECT 0.168 20.088 96.601 20.136 ;
      RECT 0.168 20.472 96.601 20.520 ;
      RECT 0.168 20.856 96.601 20.904 ;
      RECT 0.168 21.240 96.601 21.288 ;
      RECT 0.168 21.624 96.601 21.672 ;
      RECT 0.168 22.008 96.601 22.056 ;
      RECT 0.168 22.392 96.601 22.440 ;
      RECT 0.168 22.776 96.601 22.824 ;
      RECT 0.168 23.160 96.601 23.208 ;
      RECT 0.168 23.544 96.601 23.592 ;
      RECT 0.168 23.928 96.601 23.976 ;
      RECT 0.168 24.312 96.601 24.360 ;
      RECT 0.168 24.696 96.601 24.744 ;
      RECT 0.168 25.080 96.601 25.128 ;
      RECT 0.168 25.464 96.601 25.512 ;
      RECT 0.168 25.848 96.601 25.896 ;
      RECT 0.168 26.232 96.601 26.280 ;
      RECT 0.168 26.616 96.601 26.664 ;
      RECT 0.168 27.000 96.601 27.048 ;
      RECT 0.168 27.384 96.601 27.432 ;
      RECT 0.168 27.768 96.601 27.816 ;
      RECT 0.168 28.152 96.601 28.200 ;
      RECT 0.168 28.536 96.601 28.584 ;
      RECT 0.168 28.920 96.601 28.968 ;
      RECT 0.168 29.304 96.601 29.352 ;
      RECT 0.168 29.688 96.601 29.736 ;
      RECT 0.168 30.072 96.601 30.120 ;
      RECT 0.168 30.456 96.601 30.504 ;
      RECT 0.168 30.840 96.601 30.888 ;
      RECT 0.168 31.224 96.601 31.272 ;
      RECT 0.168 31.608 96.601 31.656 ;
      RECT 0.168 31.992 96.601 32.040 ;
      RECT 0.168 32.376 96.601 32.424 ;
      RECT 0.168 32.760 96.601 32.808 ;
      RECT 0.168 33.144 96.601 33.192 ;
      RECT 0.168 33.528 96.601 33.576 ;
      RECT 0.168 33.912 96.601 33.960 ;
      RECT 0.168 34.296 96.601 34.344 ;
      RECT 0.168 34.680 96.601 34.728 ;
      RECT 0.168 35.064 96.601 35.112 ;
      RECT 0.168 35.448 96.601 35.496 ;
      RECT 0.168 35.832 96.601 35.880 ;
      RECT 0.168 36.216 96.601 36.264 ;
      RECT 0.168 36.600 96.601 36.648 ;
      RECT 0.168 36.984 96.601 37.032 ;
      RECT 0.168 37.368 96.601 37.416 ;
      RECT 0.168 37.752 96.601 37.800 ;
      RECT 0.168 38.136 96.601 38.184 ;
      RECT 0.168 38.520 96.601 38.568 ;
      RECT 0.168 38.904 96.601 38.952 ;
      RECT 0.168 39.288 96.601 39.336 ;
      RECT 0.168 39.672 96.601 39.720 ;
      RECT 0.168 40.056 96.601 40.104 ;
      RECT 0.168 40.440 96.601 40.488 ;
      RECT 0.168 40.824 96.601 40.872 ;
      RECT 0.168 41.208 96.601 41.256 ;
      RECT 0.168 41.592 96.601 41.640 ;
      RECT 0.168 41.976 96.601 42.024 ;
      RECT 0.168 42.360 96.601 42.408 ;
      RECT 0.168 42.744 96.601 42.792 ;
      RECT 0.168 43.128 96.601 43.176 ;
      RECT 0.168 43.512 96.601 43.560 ;
      RECT 0.168 43.896 96.601 43.944 ;
      RECT 0.168 44.280 96.601 44.328 ;
      RECT 0.168 44.664 96.601 44.712 ;
      RECT 0.168 45.048 96.601 45.096 ;
      RECT 0.168 45.432 96.601 45.480 ;
      RECT 0.168 45.816 96.601 45.864 ;
      RECT 0.168 46.200 96.601 46.248 ;
      RECT 0.168 46.584 96.601 46.632 ;
      RECT 0.168 46.968 96.601 47.016 ;
      RECT 0.168 47.352 96.601 47.400 ;
      RECT 0.168 47.736 96.601 47.784 ;
      RECT 0.168 48.120 96.601 48.168 ;
      RECT 0.168 48.504 96.601 48.552 ;
      RECT 0.168 48.888 96.601 48.936 ;
      RECT 0.168 49.272 96.601 49.320 ;
      RECT 0.168 49.656 96.601 49.704 ;
      RECT 0.168 50.040 96.601 50.088 ;
      RECT 0.168 50.424 96.601 50.472 ;
      RECT 0.168 50.808 96.601 50.856 ;
      RECT 0.168 51.192 96.601 51.240 ;
      RECT 0.168 51.576 96.601 51.624 ;
      RECT 0.168 51.960 96.601 52.008 ;
      RECT 0.168 52.344 96.601 52.392 ;
      RECT 0.168 52.728 96.601 52.776 ;
      RECT 0.168 53.112 96.601 53.160 ;
      RECT 0.168 53.496 96.601 53.544 ;
      RECT 0.168 53.880 96.601 53.928 ;
      RECT 0.168 54.264 96.601 54.312 ;
      RECT 0.168 54.648 96.601 54.696 ;
      RECT 0.168 55.032 96.601 55.080 ;
      RECT 0.168 55.416 96.601 55.464 ;
      RECT 0.168 55.800 96.601 55.848 ;
      RECT 0.168 56.184 96.601 56.232 ;
      RECT 0.168 56.568 96.601 56.616 ;
      RECT 0.168 56.952 96.601 57.000 ;
      RECT 0.168 57.336 96.601 57.384 ;
      RECT 0.168 57.720 96.601 57.768 ;
      RECT 0.168 58.104 96.601 58.152 ;
      RECT 0.168 58.488 96.601 58.536 ;
      RECT 0.168 58.872 96.601 58.920 ;
      RECT 0.168 59.256 96.601 59.304 ;
      RECT 0.168 59.640 96.601 59.688 ;
      RECT 0.168 60.024 96.601 60.072 ;
      RECT 0.168 60.408 96.601 60.456 ;
      RECT 0.168 60.792 96.601 60.840 ;
      RECT 0.168 61.176 96.601 61.224 ;
      RECT 0.168 61.560 96.601 61.608 ;
      RECT 0.168 61.944 96.601 61.992 ;
      RECT 0.168 62.328 96.601 62.376 ;
      RECT 0.168 62.712 96.601 62.760 ;
      RECT 0.168 63.096 96.601 63.144 ;
      RECT 0.168 63.480 96.601 63.528 ;
      RECT 0.168 63.864 96.601 63.912 ;
      RECT 0.168 64.248 96.601 64.296 ;
      RECT 0.168 64.632 96.601 64.680 ;
      RECT 0.168 65.016 96.601 65.064 ;
      RECT 0.168 65.400 96.601 65.448 ;
      RECT 0.168 65.784 96.601 65.832 ;
      RECT 0.168 66.168 96.601 66.216 ;
      RECT 0.168 66.552 96.601 66.600 ;
      RECT 0.168 66.936 96.601 66.984 ;
      RECT 0.168 67.320 96.601 67.368 ;
      RECT 0.168 67.704 96.601 67.752 ;
      RECT 0.168 68.088 96.601 68.136 ;
      RECT 0.168 68.472 96.601 68.520 ;
      RECT 0.168 68.856 96.601 68.904 ;
      RECT 0.168 69.240 96.601 69.288 ;
      RECT 0.168 69.624 96.601 69.672 ;
      RECT 0.168 70.008 96.601 70.056 ;
      RECT 0.168 70.392 96.601 70.440 ;
      RECT 0.168 70.776 96.601 70.824 ;
      RECT 0.168 71.160 96.601 71.208 ;
      RECT 0.168 71.544 96.601 71.592 ;
      RECT 0.168 71.928 96.601 71.976 ;
      RECT 0.168 72.312 96.601 72.360 ;
      RECT 0.168 72.696 96.601 72.744 ;
      RECT 0.168 73.080 96.601 73.128 ;
      RECT 0.168 73.464 96.601 73.512 ;
      RECT 0.168 73.848 96.601 73.896 ;
      RECT 0.168 74.232 96.601 74.280 ;
      RECT 0.168 74.616 96.601 74.664 ;
      RECT 0.168 75.000 96.601 75.048 ;
      RECT 0.168 75.384 96.601 75.432 ;
      RECT 0.168 75.768 96.601 75.816 ;
      RECT 0.168 76.152 96.601 76.200 ;
      RECT 0.168 76.536 96.601 76.584 ;
      RECT 0.168 76.920 96.601 76.968 ;
      RECT 0.168 77.304 96.601 77.352 ;
      RECT 0.168 77.688 96.601 77.736 ;
      RECT 0.168 78.072 96.601 78.120 ;
      RECT 0.168 78.456 96.601 78.504 ;
      RECT 0.168 78.840 96.601 78.888 ;
      RECT 0.168 79.224 96.601 79.272 ;
      RECT 0.168 79.608 96.601 79.656 ;
      RECT 0.168 79.992 96.601 80.040 ;
      RECT 0.168 80.376 96.601 80.424 ;
      RECT 0.168 80.760 96.601 80.808 ;
      RECT 0.168 81.144 96.601 81.192 ;
      RECT 0.168 81.528 96.601 81.576 ;
      RECT 0.168 81.912 96.601 81.960 ;
      RECT 0.168 82.296 96.601 82.344 ;
      RECT 0.168 82.680 96.601 82.728 ;
      RECT 0.168 83.064 96.601 83.112 ;
      RECT 0.168 83.448 96.601 83.496 ;
      RECT 0.168 83.832 96.601 83.880 ;
      RECT 0.168 84.216 96.601 84.264 ;
      RECT 0.168 84.600 96.601 84.648 ;
      RECT 0.168 84.984 96.601 85.032 ;
      RECT 0.168 85.368 96.601 85.416 ;
      RECT 0.168 85.752 96.601 85.800 ;
      RECT 0.168 86.136 96.601 86.184 ;
      RECT 0.168 86.520 96.601 86.568 ;
      RECT 0.168 86.904 96.601 86.952 ;
      RECT 0.168 87.288 96.601 87.336 ;
      RECT 0.168 87.672 96.601 87.720 ;
      RECT 0.168 88.056 96.601 88.104 ;
      RECT 0.168 88.440 96.601 88.488 ;
      RECT 0.168 88.824 96.601 88.872 ;
      RECT 0.168 89.208 96.601 89.256 ;
      RECT 0.168 89.592 96.601 89.640 ;
      RECT 0.168 89.976 96.601 90.024 ;
      RECT 0.168 90.360 96.601 90.408 ;
      RECT 0.168 90.744 96.601 90.792 ;
      RECT 0.168 91.128 96.601 91.176 ;
      RECT 0.168 91.512 96.601 91.560 ;
      RECT 0.168 91.896 96.601 91.944 ;
      RECT 0.168 92.280 96.601 92.328 ;
      RECT 0.168 92.664 96.601 92.712 ;
      RECT 0.168 93.048 96.601 93.096 ;
      RECT 0.168 93.432 96.601 93.480 ;
      RECT 0.168 93.816 96.601 93.864 ;
      RECT 0.168 94.200 96.601 94.248 ;
      RECT 0.168 94.584 96.601 94.632 ;
      RECT 0.168 94.968 96.601 95.016 ;
      RECT 0.168 95.352 96.601 95.400 ;
      RECT 0.168 95.736 96.601 95.784 ;
      RECT 0.168 96.120 96.601 96.168 ;
      RECT 0.168 96.504 96.601 96.552 ;
      RECT 0.168 96.888 96.601 96.936 ;
      RECT 0.168 97.272 96.601 97.320 ;
      RECT 0.168 97.656 96.601 97.704 ;
      RECT 0.168 98.040 96.601 98.088 ;
      RECT 0.168 98.424 96.601 98.472 ;
      RECT 0.168 98.808 96.601 98.856 ;
      RECT 0.168 99.192 96.601 99.240 ;
      RECT 0.168 99.576 96.601 99.624 ;
      RECT 0.168 99.960 96.601 100.008 ;
      RECT 0.168 100.344 96.601 100.392 ;
      RECT 0.168 100.728 96.601 100.776 ;
      RECT 0.168 101.112 96.601 101.160 ;
      RECT 0.168 101.496 96.601 101.544 ;
      RECT 0.168 101.880 96.601 101.928 ;
      RECT 0.168 102.264 96.601 102.312 ;
      RECT 0.168 102.648 96.601 102.696 ;
      RECT 0.168 103.032 96.601 103.080 ;
      RECT 0.168 103.416 96.601 103.464 ;
      RECT 0.168 103.800 96.601 103.848 ;
      RECT 0.168 104.184 96.601 104.232 ;
      RECT 0.168 104.568 96.601 104.616 ;
      RECT 0.168 104.952 96.601 105.000 ;
      RECT 0.168 105.336 96.601 105.384 ;
      RECT 0.168 105.720 96.601 105.768 ;
      RECT 0.168 106.104 96.601 106.152 ;
      RECT 0.168 106.488 96.601 106.536 ;
      RECT 0.168 106.872 96.601 106.920 ;
      RECT 0.168 107.256 96.601 107.304 ;
      RECT 0.168 107.640 96.601 107.688 ;
      RECT 0.168 108.024 96.601 108.072 ;
      RECT 0.168 108.408 96.601 108.456 ;
      RECT 0.168 108.792 96.601 108.840 ;
      RECT 0.168 109.176 96.601 109.224 ;
      RECT 0.168 109.560 96.601 109.608 ;
      RECT 0.168 109.944 96.601 109.992 ;
      RECT 0.168 110.328 96.601 110.376 ;
      RECT 0.168 110.712 96.601 110.760 ;
      RECT 0.168 111.096 96.601 111.144 ;
      RECT 0.168 111.480 96.601 111.528 ;
      RECT 0.168 111.864 96.601 111.912 ;
      RECT 0.168 112.248 96.601 112.296 ;
      RECT 0.168 112.632 96.601 112.680 ;
      RECT 0.168 113.016 96.601 113.064 ;
      RECT 0.168 113.400 96.601 113.448 ;
      RECT 0.168 113.784 96.601 113.832 ;
      RECT 0.168 114.168 96.601 114.216 ;
      RECT 0.168 114.552 96.601 114.600 ;
      RECT 0.168 114.936 96.601 114.984 ;
      RECT 0.168 115.320 96.601 115.368 ;
      RECT 0.168 115.704 96.601 115.752 ;
      RECT 0.168 116.088 96.601 116.136 ;
      RECT 0.168 116.472 96.601 116.520 ;
      RECT 0.168 116.856 96.601 116.904 ;
      RECT 0.168 117.240 96.601 117.288 ;
      RECT 0.168 117.624 96.601 117.672 ;
      RECT 0.168 118.008 96.601 118.056 ;
      RECT 0.168 118.392 96.601 118.440 ;
      RECT 0.168 118.776 96.601 118.824 ;
      RECT 0.168 119.160 96.601 119.208 ;
      RECT 0.168 119.544 96.601 119.592 ;
      RECT 0.168 119.928 96.601 119.976 ;
      RECT 0.168 120.312 96.601 120.360 ;
      RECT 0.168 120.696 96.601 120.744 ;
      RECT 0.168 121.080 96.601 121.128 ;
      RECT 0.168 121.464 96.601 121.512 ;
      RECT 0.168 121.848 96.601 121.896 ;
      RECT 0.168 122.232 96.601 122.280 ;
      RECT 0.168 122.616 96.601 122.664 ;
      RECT 0.168 123.000 96.601 123.048 ;
      RECT 0.168 123.384 96.601 123.432 ;
      RECT 0.168 123.768 96.601 123.816 ;
      RECT 0.168 124.152 96.601 124.200 ;
      RECT 0.168 124.536 96.601 124.584 ;
      RECT 0.168 124.920 96.601 124.968 ;
      RECT 0.168 125.304 96.601 125.352 ;
      RECT 0.168 125.688 96.601 125.736 ;
      RECT 0.168 126.072 96.601 126.120 ;
      RECT 0.168 126.456 96.601 126.504 ;
      RECT 0.168 126.840 96.601 126.888 ;
      RECT 0.168 127.224 96.601 127.272 ;
      RECT 0.168 127.608 96.601 127.656 ;
      RECT 0.168 127.992 96.601 128.040 ;
      RECT 0.168 128.376 96.601 128.424 ;
      RECT 0.168 128.760 96.601 128.808 ;
      RECT 0.168 129.144 96.601 129.192 ;
      RECT 0.168 129.528 96.601 129.576 ;
      RECT 0.168 129.912 96.601 129.960 ;
      RECT 0.168 130.296 96.601 130.344 ;
      RECT 0.168 130.680 96.601 130.728 ;
      RECT 0.168 131.064 96.601 131.112 ;
      RECT 0.168 131.448 96.601 131.496 ;
      RECT 0.168 131.832 96.601 131.880 ;
      RECT 0.168 132.216 96.601 132.264 ;
      RECT 0.168 132.600 96.601 132.648 ;
      RECT 0.168 132.984 96.601 133.032 ;
      RECT 0.168 133.368 96.601 133.416 ;
      RECT 0.168 133.752 96.601 133.800 ;
      RECT 0.168 134.136 96.601 134.184 ;
      RECT 0.168 134.520 96.601 134.568 ;
      RECT 0.168 134.904 96.601 134.952 ;
      RECT 0.168 135.288 96.601 135.336 ;
      RECT 0.168 135.672 96.601 135.720 ;
      RECT 0.168 136.056 96.601 136.104 ;
      RECT 0.168 136.440 96.601 136.488 ;
      RECT 0.168 136.824 96.601 136.872 ;
      RECT 0.168 137.208 96.601 137.256 ;
      RECT 0.168 137.592 96.601 137.640 ;
      RECT 0.168 137.976 96.601 138.024 ;
      RECT 0.168 138.360 96.601 138.408 ;
      RECT 0.168 138.744 96.601 138.792 ;
      RECT 0.168 139.128 96.601 139.176 ;
      RECT 0.168 139.512 96.601 139.560 ;
      RECT 0.168 139.896 96.601 139.944 ;
      RECT 0.168 140.280 96.601 140.328 ;
      RECT 0.168 140.664 96.601 140.712 ;
      RECT 0.168 141.048 96.601 141.096 ;
      RECT 0.168 141.432 96.601 141.480 ;
      RECT 0.168 141.816 96.601 141.864 ;
      RECT 0.168 142.200 96.601 142.248 ;
      RECT 0.168 142.584 96.601 142.632 ;
      RECT 0.168 142.968 96.601 143.016 ;
      RECT 0.168 143.352 96.601 143.400 ;
      RECT 0.168 143.736 96.601 143.784 ;
      RECT 0.168 144.120 96.601 144.168 ;
      RECT 0.168 144.504 96.601 144.552 ;
      RECT 0.168 144.888 96.601 144.936 ;
      RECT 0.168 145.272 96.601 145.320 ;
      RECT 0.168 145.656 96.601 145.704 ;
      RECT 0.168 146.040 96.601 146.088 ;
      RECT 0.168 146.424 96.601 146.472 ;
      RECT 0.168 146.808 96.601 146.856 ;
      RECT 0.168 147.192 96.601 147.240 ;
      RECT 0.168 147.576 96.601 147.624 ;
      RECT 0.168 147.960 96.601 148.008 ;
      RECT 0.168 148.344 96.601 148.392 ;
      RECT 0.168 148.728 96.601 148.776 ;
      RECT 0.168 149.112 96.601 149.160 ;
      RECT 0.168 149.496 96.601 149.544 ;
      RECT 0.168 149.880 96.601 149.928 ;
      RECT 0.168 150.264 96.601 150.312 ;
      RECT 0.168 150.648 96.601 150.696 ;
      RECT 0.168 151.032 96.601 151.080 ;
      RECT 0.168 151.416 96.601 151.464 ;
      RECT 0.168 151.800 96.601 151.848 ;
      RECT 0.168 152.184 96.601 152.232 ;
      RECT 0.168 152.568 96.601 152.616 ;
      RECT 0.168 152.952 96.601 153.000 ;
      RECT 0.168 153.336 96.601 153.384 ;
      RECT 0.168 153.720 96.601 153.768 ;
      RECT 0.168 154.104 96.601 154.152 ;
      RECT 0.168 154.488 96.601 154.536 ;
      RECT 0.168 154.872 96.601 154.920 ;
      RECT 0.168 155.256 96.601 155.304 ;
      RECT 0.168 155.640 96.601 155.688 ;
      RECT 0.168 156.024 96.601 156.072 ;
      RECT 0.168 156.408 96.601 156.456 ;
      RECT 0.168 156.792 96.601 156.840 ;
      RECT 0.168 157.176 96.601 157.224 ;
      RECT 0.168 157.560 96.601 157.608 ;
      RECT 0.168 157.944 96.601 157.992 ;
      RECT 0.168 158.328 96.601 158.376 ;
      RECT 0.168 158.712 96.601 158.760 ;
      RECT 0.168 159.096 96.601 159.144 ;
      RECT 0.168 159.480 96.601 159.528 ;
      RECT 0.168 159.864 96.601 159.912 ;
      RECT 0.168 160.248 96.601 160.296 ;
      RECT 0.168 160.632 96.601 160.680 ;
      RECT 0.168 161.016 96.601 161.064 ;
      RECT 0.168 161.400 96.601 161.448 ;
      RECT 0.168 161.784 96.601 161.832 ;
      RECT 0.168 162.168 96.601 162.216 ;
      RECT 0.168 162.552 96.601 162.600 ;
      RECT 0.168 162.936 96.601 162.984 ;
      RECT 0.168 163.320 96.601 163.368 ;
      RECT 0.168 163.704 96.601 163.752 ;
      RECT 0.168 164.088 96.601 164.136 ;
      RECT 0.168 164.472 96.601 164.520 ;
      RECT 0.168 164.856 96.601 164.904 ;
      RECT 0.168 165.240 96.601 165.288 ;
      RECT 0.168 165.624 96.601 165.672 ;
    END
  END VDD
  OBS
    LAYER M1 ;
    RECT 0 0 96.769 165.888 ;
    LAYER M2 ;
    RECT 0 0 96.769 165.888 ;
    LAYER M3 ;
    RECT 0 0 96.769 165.888 ;
    LAYER M4 ;
    RECT 0 0 96.769 165.888 ;
  END
END fakeram_w16_l8192

END LIBRARY
